VERSION 5.7 ;
  NOWIREEXTENSIONATPIN ON ;
  DIVIDERCHAR "/" ;
  BUSBITCHARS "[]" ;
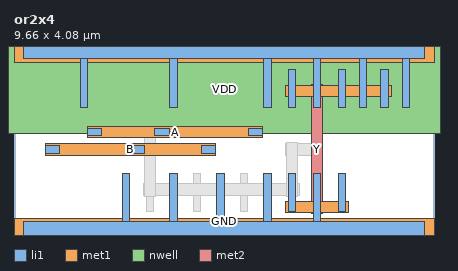
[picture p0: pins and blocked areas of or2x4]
MACRO or2x4
  CLASS BLOCK ;
  FOREIGN or2x4 ;
  ORIGIN 0.000 0.000 ;
  SIZE 9.660 BY 4.080 ;
  PIN A
    ANTENNAGATEAREA 1.495200 ;
    PORT
      LAYER li1 ;
        RECT 1.685 2.145 2.015 2.315 ;
        RECT 3.235 2.145 3.565 2.315 ;
        RECT 5.395 2.145 5.725 2.315 ;
      LAYER met1 ;
        RECT 1.690 2.100 5.720 2.360 ;
    END
  END A
  PIN B
    ANTENNAGATEAREA 1.495200 ;
    PORT
      LAYER li1 ;
        RECT 0.725 1.745 1.055 1.915 ;
        RECT 2.675 1.745 3.005 1.915 ;
        RECT 4.315 1.745 4.645 1.915 ;
      LAYER met1 ;
        RECT 0.730 1.700 4.640 1.960 ;
    END
  END B
  PIN VDD
    ANTENNADIFFAREA 4.288800 ;
    PORT
      LAYER nwell ;
        RECT -0.230 2.200 9.890 4.410 ;
      LAYER li1 ;
        RECT 0.210 3.915 9.450 4.245 ;
        RECT 1.525 2.800 1.695 3.915 ;
        RECT 3.585 2.800 3.755 3.915 ;
        RECT 5.745 2.800 5.915 3.915 ;
        RECT 6.885 2.800 7.055 3.915 ;
        RECT 7.945 2.800 8.115 3.915 ;
        RECT 8.925 2.800 9.095 3.915 ;
      LAYER met1 ;
        RECT 0.000 3.840 9.660 4.320 ;
    END
  END VDD
  PIN GND
    ANTENNADIFFAREA 3.877200 ;
    PORT
      LAYER li1 ;
        RECT 2.485 0.165 2.655 1.280 ;
        RECT 3.585 0.165 3.755 1.280 ;
        RECT 4.665 0.165 4.835 1.280 ;
        RECT 5.745 0.165 5.915 1.280 ;
        RECT 6.885 0.165 7.055 1.280 ;
        RECT 0.210 -0.165 9.450 0.165 ;
      LAYER met1 ;
        RECT 0.000 -0.240 9.660 0.240 ;
    END
  END GND
  PIN Y
    ANTENNADIFFAREA 1.281000 ;
    PORT
      LAYER li1 ;
        RECT 6.315 2.800 6.485 3.680 ;
        RECT 7.455 2.800 7.625 3.680 ;
        RECT 8.435 2.800 8.605 3.680 ;
        RECT 6.315 0.400 6.485 1.280 ;
        RECT 7.455 0.400 7.625 1.280 ;
      LAYER met1 ;
        RECT 6.240 3.040 8.680 3.300 ;
        RECT 6.240 0.380 7.700 0.640 ;
      LAYER met2 ;
        RECT 6.840 0.350 7.100 3.330 ;
    END
  END Y
  OBS
      LAYER li1 ;
        RECT 0.565 2.800 0.735 3.680 ;
        RECT 1.045 2.800 1.215 3.680 ;
        RECT 2.005 2.800 2.175 3.680 ;
        RECT 2.485 2.800 2.655 3.680 ;
        RECT 3.045 2.800 3.215 3.680 ;
        RECT 4.125 2.800 4.295 3.680 ;
        RECT 4.665 2.800 4.835 3.680 ;
        RECT 5.205 2.800 5.375 3.680 ;
        RECT 6.520 1.745 6.850 1.915 ;
        RECT 3.045 0.400 3.215 1.280 ;
        RECT 4.125 0.400 4.295 1.280 ;
        RECT 5.205 0.400 5.375 1.280 ;
      LAYER met1 ;
        RECT 0.970 3.440 5.450 3.700 ;
        RECT 0.490 3.040 4.910 3.300 ;
        RECT 6.240 1.700 6.845 1.960 ;
        RECT 2.970 0.780 6.560 1.040 ;
      LAYER met2 ;
        RECT 3.000 0.750 3.260 3.330 ;
        RECT 6.270 0.750 6.530 1.990 ;
  END
END or2x4
END LIBRARY

